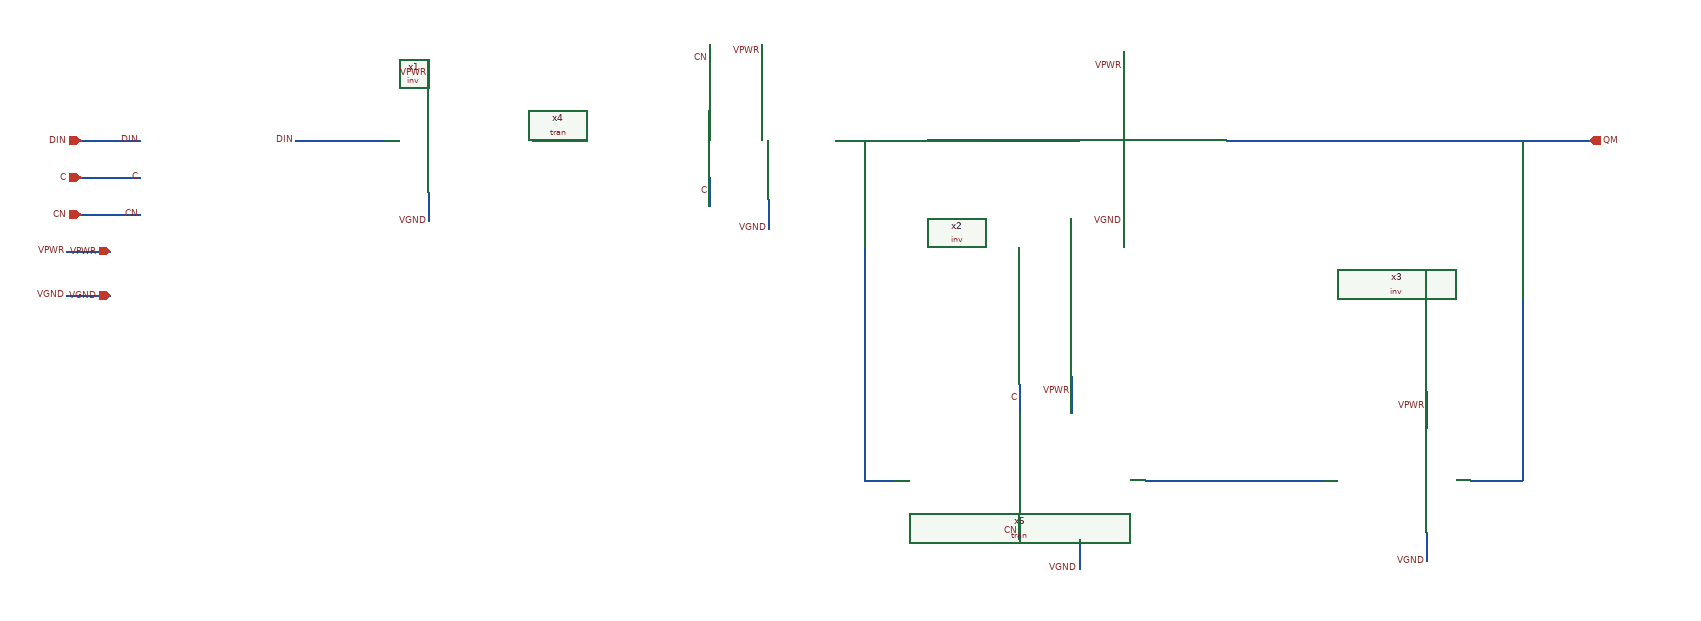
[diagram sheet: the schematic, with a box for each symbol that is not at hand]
v {xschem version=3.4.8RC file_version=1.3}
G {}
K {}
V {}
S {}
F {}
E {}
N 1010 -1150 1130 -1150 {lab=DIN}
N 1330 -1150 1400 -1150 {lab=#net1}
N 1740 -1150 2070 -1150 {lab=#net2}
N 2270 -1150 2760 -1150 {lab=QM}
N 1780 -690 1820 -690 {lab=#net2}
N 1780 -1150 1780 -690 {lab=#net2}
N 2160 -690 2400 -690 {lab=#net3}
N 2600 -690 2670 -690 {lab=QM}
N 2670 -1150 2670 -690 {lab=QM}
N 1190 -1260 1190 -1220 {lab=VPWR}
N 1190 -1080 1190 -1040 {lab=VGND}
N 1650 -1070 1650 -1030 {lab=VGND}
N 1640 -1280 1640 -1240 {lab=VPWR}
N 2130 -1270 2130 -1220 {lab=VPWR}
N 2130 -1080 2130 -1040 {lab=#net4}
N 2060 -830 2060 -780 {lab=VPWR}
N 2070 -610 2070 -570 {lab=VGND}
N 1990 -640 1990 -610 {lab=CN}
N 1990 -820 1990 -780 {lab=C}
N 2540 -810 2540 -760 {lab=VPWR}
N 2540 -620 2540 -580 {lab=VGND}
N 1570 -1100 1570 -1060 {lab=C}
N 1570 -1280 1570 -1240 {lab=CN}
N 720 -1150 800 -1150 {lab=DIN}
N 720 -1100 800 -1100 {lab=C}
N 720 -1050 800 -1050 {lab=CN}
N 700 -1000 760 -1000 {lab=VPWR}
N 700 -940 760 -940 {lab=VGND}
C {/home/sushanth/Desktop/HighSpeedScanFlop/inverter/inv.sym} 1100 -1070 0 0 {name=x1}
C {/home/sushanth/Desktop/HighSpeedScanFlop/inverter/inv.sym} 2040 -1070 0 0 {name=x2}
C {/home/sushanth/Desktop/HighSpeedScanFlop/inverter/inv.sym} 2630 -610 0 1 {name=x3}
C {/home/sushanth/projects/trans/tran.sym} 1360 -1040 0 0 {name=x4}
C {/home/sushanth/projects/trans/tran.sym} 1780 -580 0 0 {name=x5}
C {opin.sym} 2760 -1150 0 0 {name=p1 lab=QM}
C {lab_pin.sym} 1570 -1080 0 0 {name=p3 sig_type=std_logic lab=C}
C {lab_pin.sym} 1990 -800 0 0 {name=p4 sig_type=std_logic lab=C}
C {lab_pin.sym} 1570 -1260 0 0 {name=p6 sig_type=std_logic lab=CN}
C {lab_pin.sym} 1990 -620 0 0 {name=p7 sig_type=std_logic lab=CN}
C {lab_pin.sym} 1010 -1150 0 0 {name=p9 sig_type=std_logic lab=DIN}
C {ipin.sym} 720 -1150 0 0 {name=p2 lab=DIN}
C {ipin.sym} 720 -1100 0 0 {name=p5 lab=C}
C {ipin.sym} 720 -1050 0 0 {name=p8 lab=CN}
C {iopin.sym} 760 -1000 0 0 {name=p10 lab=VPWR}
C {iopin.sym} 760 -940 0 0 {name=p11 lab=VGND}
C {lab_pin.sym} 800 -1150 0 0 {name=p12 sig_type=std_logic lab=DIN}
C {lab_pin.sym} 800 -1100 0 0 {name=p13 sig_type=std_logic lab=C}
C {lab_pin.sym} 800 -1050 0 0 {name=p14 sig_type=std_logic lab=CN}
C {lab_pin.sym} 700 -1000 0 0 {name=p15 sig_type=std_logic lab=VPWR}
C {lab_pin.sym} 700 -940 0 0 {name=p16 sig_type=std_logic lab=VGND}
C {lab_pin.sym} 1190 -1240 0 0 {name=p17 sig_type=std_logic lab=VPWR}
C {lab_pin.sym} 1640 -1270 0 0 {name=p18 sig_type=std_logic lab=VPWR}
C {lab_pin.sym} 2130 -1250 0 0 {name=p19 sig_type=std_logic lab=VPWR}
C {lab_pin.sym} 2540 -790 0 0 {name=p20 sig_type=std_logic lab=VPWR}
C {lab_pin.sym} 2060 -810 0 0 {name=p21 sig_type=std_logic lab=VPWR}
C {lab_pin.sym} 1190 -1040 0 0 {name=p22 sig_type=std_logic lab=VGND}
C {lab_pin.sym} 1650 -1030 0 0 {name=p23 sig_type=std_logic lab=VGND}
C {lab_pin.sym} 2070 -570 0 0 {name=p25 sig_type=std_logic lab=VGND}
C {lab_pin.sym} 2540 -580 0 0 {name=p26 sig_type=std_logic lab=VGND}
C {lab_pin.sym} 2130 -1040 0 0 {name=p24 sig_type=std_logic lab=VGND}
